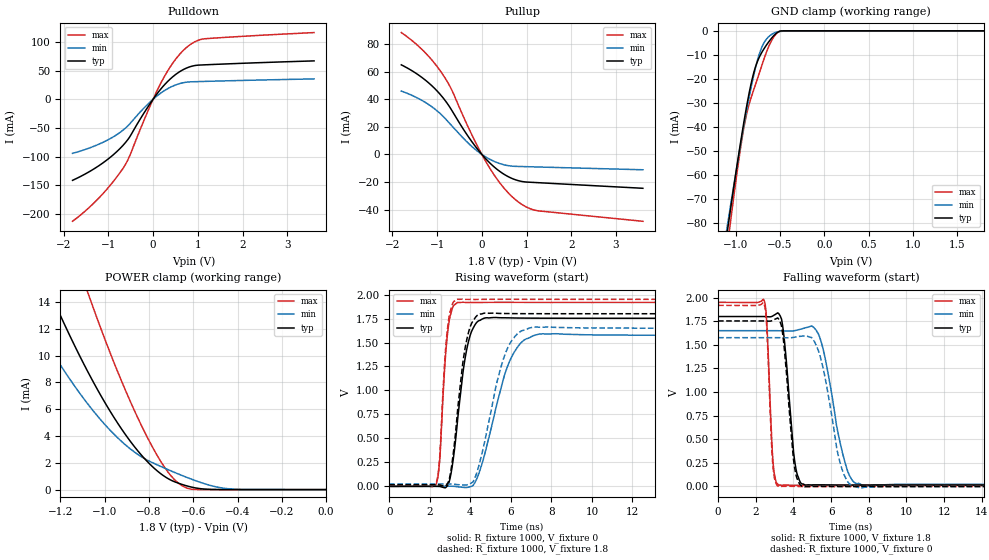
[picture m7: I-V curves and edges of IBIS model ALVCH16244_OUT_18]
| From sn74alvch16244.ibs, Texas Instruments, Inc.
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[Model]   ALVCH16244_OUT_18
Model_type  3-state
Enable   Active-Low
Vref =   0
Rref =   1000
Cref =   30p
Vmeas =   0.9
| variable   typ   min   max
C_comp   7.36pF   6.56pF   8.29pF
| C_pullup   8.44pF   7.01pF   9.20pF
| C_pulldown   11.41pF   8.44pF   14.80pF
| C_tri-state   7.36pF   6.56pF   8.29pF
[Temperature Range]   40   100   -40
| Ambient temperature   25   85   -40
[Voltage range]   1.8   1.65   1.95
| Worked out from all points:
|   slope of the pulldown table from 0 to 0.27 V, typ, clamps not added: 10.2 ohm
|   slope of the pullup table from 0 to 0.27 V, typ, clamps not added: 30.2 ohm
|   GND clamp passes 1 mA (typ) near -0.54 V on its own axis
|   POWER clamp passes 1 mA (typ) near -0.73 V on its own axis
|   rising waveform, R_fixture 1000, V_fixture 0: 20-80 % time 601ps typ, 1.17ns min, 324ps max; typ from 0 V to 1.75 V
|   falling waveform, R_fixture 1000, V_fixture 1.8: 20-80 % time 434ps typ, 895ps min, 245ps max; typ from 1.8 V to 0.016 V
|   rising waveform, R_fixture 1000, V_fixture 1.8: 20-80 % time 569ps typ, 1.05ns min, 316ps max; typ from 0.016 V to 1.8 V
|   falling waveform, R_fixture 1000, V_fixture 0: 20-80 % time 433ps typ, 831ps min, 234ps max; typ from 1.75 V to 0 V
[GND Clamp]
| ALVCH16244_OUT_18
|   Voltage   I(typ)   I(min)   I(max)
-1.8V     -279.2mA   -258.4mA   -312.7mA
-1.09V    -82.1mA    -79.94mA   -88.35mA
-1.075V   -78.25mA   -76.44mA   -83.98mA
-1.055V   -73.15mA   -71.81mA   -78.22mA
-915mV    -39.48mA   -40.86mA   -41.77mA
-870mV    -29.95mA   -31.73mA   -33.49mA
-815mV    -20.09mA   -21.51mA   -26.49mA
-765mV    -13.71mA   -13.6mA    -21.01mA
-710mV    -9.262mA   -7.21mA    -14.9mA
-585mV    -2.6mA     -1.263mA   -3.417mA
-485mV    -33.17uA   -215.5uA   -23.48uA
1.8V      60.47pA    9.424nA    28.01pA
[POWER Clamp]
| ALVCH16244_OUT_18
|   Voltage   I(typ)   I(min)   I(max)
-1.8V     39.51mA    28.78mA    57.18mA
-1.39V    20.42mA    14.63mA    31.28mA
-1.23V    14.08mA    10.07mA    22.39mA
-1.08V    8.91mA     6.466mA    14.87mA
-1.065V   8.441mA    6.147mA    14.17mA
-955mV    5.302mA    4.082mA    9.347mA
-860mV    3.083mA    2.735mA    5.684mA
-750mV    1.224mA    1.751mA    2.186mA
-665mV    466.1uA    1.149mA    454.2uA
-610mV    194.7uA    789.6uA    32.77uA
-455mV    1.47uA     87.26uA    53.39nA
-16.28fV  60.47pA    287pA      33.61pA
[Pulldown]
| ALVCH16244_OUT_18
|   Voltage   I(typ)   I(min)   I(max)
-1.8V     -141.4mA   -94.33mA   -212.9mA
-1.195V   -115mA     -77.76mA   -171mA
-905mV    -97.86mA   -66.26mA   -145mA
-665mV    -79.81mA   -53.39mA   -119.8mA
-530mV    -66.51mA   -43.55mA   -100.1mA
-105mV    -12.13mA   -7.634mA   -18.73mA
200mV     20.41mA    12.38mA    32.16mA
495mV     42.75mA    24.8mA     68.98mA
790mV     55.87mA    30.28mA    93.18mA
970mV     59.35mA    30.84mA    101.8mA
1.155V    60.2mA     31.26mA    105.7mA
3.6V      67.09mA    35.62mA    116.5mA
[Pullup]
| ALVCH16244_OUT_18
|   Voltage   I(typ)   I(min)   I(max)
-1.8V     64.98mA    45.95mA    88.4mA
-1.305V   54.98mA    38.53mA    75.09mA
-1.09V    48.97mA    33.9mA     67.43mA
-900mV    42.35mA    28.69mA    59.27mA
-675mV    32.13mA    20.88mA    46.91mA
-280mV    11.84mA    7.43mA     18.08mA
120mV     -4.3mA     -2.474mA   -6.918mA
455mV     -13.55mA   -7.178mA   -22.84mA
795mV     -18.85mA   -8.713mA   -33.97mA
1.025V    -20.11mA   -8.923mA   -38.62mA
1.255V    -20.5mA    -9.129mA   -40.95mA
3.6V      -24.58mA   -11.14mA   -48.53mA
[Ramp]
| ALVCH16244_OUT_18
| variable   typ   min   max
dV/dt_r   1.06/6.34E-10   0.96/1.25E-09   1.15/3.31E-10
dV/dt_f   1.09/4.48E-10   1.01/1.00E-09   1.18/2.52E-10
R_load = 1000
[Rising Waveform]
| ALVCH16244_OUT_18
R_fixture =   1000
C_fixture =   0
L_fixture =   0
V_fixture =   0
V_fixture_min = 0
V_fixture_max = 0
|   Time   V(typ)   V(min)   V(max)
0s        316.9pV    1.692nV    220.5pV
2.32ns    670.7uV    236.4uV    23.89mV
2.5ns     -1.241mV   1.195mV    301.7mV
2.895ns   16.62mV    1.644mV    1.628V
3.39ns    730.7mV    -4.61mV    1.918V
3.815ns   1.419V     -12.14mV   1.918V
4.3ns     1.706V     69.65mV    1.917V
5.94ns    1.757V     1.306V     1.919V
7.395ns   1.754V     1.588V     1.918V
50ns      1.753V     1.576V     1.918V
[Falling Waveform]
| ALVCH16244_OUT_18
R_fixture =   1000
C_fixture =   0
L_fixture =   0
V_fixture =   1.8
V_fixture_min = 1.65
V_fixture_max = 1.95
|   Time   V(typ)   V(min)   V(max)
0s        1.8V       1.65V      1.95V
2.455ns   1.8V       1.65V      1.963V
2.92ns    1.808V     1.65V      255.2mV
3.235ns   1.827V     1.649V     13.86mV
4.09ns    238.3mV    1.652V     12.47mV
4.635ns   14.65mV    1.68V      11.07mV
5.475ns   17.28mV    1.53V      10.76mV
6.88ns    15.66mV    160.6mV    10.97mV
7.805ns   15.64mV    5.683mV    11.06mV
50ns      15.91mV    23.52mV    11.08mV
[Rising Waveform]
| ALVCH16244_OUT_18
R_fixture =   1000
C_fixture =   0
L_fixture =   0
V_fixture =   1.8
V_fixture_min = 1.65
V_fixture_max = 1.95
|   Time   V(typ)   V(min)   V(max)
0s        15.91mV    23.52mV    11.08mV
2.32ns    16.16mV    23.76mV    36.86mV
2.495ns   14.24mV    24.48mV    319mV
2.885ns   33.49mV    24.16mV    1.666V
3.38ns    811.5mV    18.25mV    1.952V
3.785ns   1.489V     13.59mV    1.95V
4.265ns   1.766V     108.8mV    1.949V
5.725ns   1.802V     1.384V     1.951V
7.07ns    1.8V       1.659V     1.95V
50ns      1.8V       1.65V      1.95V
[Falling Waveform]
| ALVCH16244_OUT_18
R_fixture =   1000
C_fixture =   0
L_fixture =   0
V_fixture =   0
V_fixture_min = 0
V_fixture_max = 0
|   Time   V(typ)   V(min)   V(max)
0s        1.753V     1.576V     1.918V
2.45ns    1.753V     1.576V     1.928V
2.895ns   1.758V     1.576V     259.7mV
3.18ns    1.782V     1.576V     3.239mV
4.065ns   198.6mV    1.581V     1.222mV
4.59ns    -2.9mV     1.594V     -35.99uV
5.42ns    911.6uV    1.377V     -328.6uV
6.615ns   -233.9uV   162.2mV    -123.9uV
7.48ns    -259.9uV   -12.72mV   -33.54uV
50ns      2.599nV    -2.337nV   -4.936nV
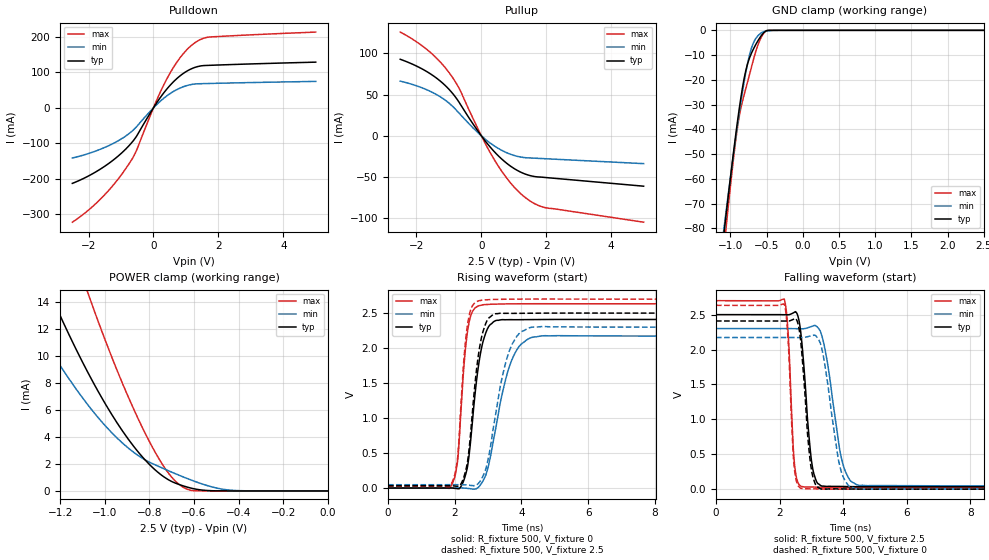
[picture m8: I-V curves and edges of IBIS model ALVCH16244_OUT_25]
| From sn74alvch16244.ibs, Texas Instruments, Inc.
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[Model]   ALVCH16244_OUT_25
Model_type  3-state
Enable   Active-Low
Vref =   0
Rref =   500
Cref =   30p
Vmeas =   1.25
| variable   typ   min   max
C_comp   7.09pF   6.28pF   8.16pF
| C_pullup   8.26pF   6.89pF   9.11pF
| C_pulldown   10.90pF   8.43pF   13.84pF
| C_tri-state   7.09pF   6.28pF   8.16pF
[Temperature Range]   40   100   -40
| Ambient temperature   25   85   -40
[Voltage range]   2.5   2.3   2.7
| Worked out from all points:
|   slope of the pulldown table from 0 to 0.375 V, typ, clamps not added: 7.65 ohm
|   slope of the pullup table from 0 to 0.375 V, typ, clamps not added: 20.6 ohm
|   GND clamp passes 1 mA (typ) near -0.54 V on its own axis
|   POWER clamp passes 1 mA (typ) near -0.73 V on its own axis
|   rising waveform, R_fixture 500, V_fixture 0: 20-80 % time 340ps typ, 575ps min, 236ps max; typ from 0 V to 2.41 V
|   falling waveform, R_fixture 500, V_fixture 2.5: 20-80 % time 255ps typ, 430ps min, 157ps max; typ from 2.5 V to 0.034 V
|   rising waveform, R_fixture 500, V_fixture 2.5: 20-80 % time 321ps typ, 525ps min, 230ps max; typ from 0.034 V to 2.5 V
|   falling waveform, R_fixture 500, V_fixture 0: 20-80 % time 241ps typ, 407ps min, 154ps max; typ from 2.41 V to 0 V
[GND Clamp]
| ALVCH16244_OUT_25
|   Voltage   I(typ)   I(min)   I(max)
-2.5V     -484.4mA   -444.2mA   -546.2mA
-1.085V   -80.82mA   -78.77mA   -86.89mA
-1.07V    -76.97mA   -75.28mA   -82.53mA
-1.05V    -71.89mA   -70.66mA   -76.79mA
-915mV    -39.48mA   -40.86mA   -41.77mA
-870mV    -29.95mA   -31.73mA   -33.49mA
-810mV    -19.33mA   -20.65mA   -25.93mA
-755mV    -12.74mA   -12.24mA   -19.91mA
-700mV    -8.616mA   -6.354mA   -13.78mA
-560mV    -1.618mA   -798.8uA   -2.03mA
-485mV    -33.17uA   -215.5uA   -23.48uA
2.5V      83.81pA    43.81nA    39.19pA
[POWER Clamp]
| ALVCH16244_OUT_25
|   Voltage   I(typ)   I(min)   I(max)
-2.5V     78.16mA    58.07mA    108.2mA
-1.385V   20.21mA    14.48mA    30.99mA
-1.24V    14.46mA    10.33mA    22.92mA
-1.08V    8.91mA     6.466mA    14.87mA
-1.065V   8.441mA    6.147mA    14.17mA
-945mV    5.045mA    3.92mA     8.938mA
-855mV    2.981mA    2.677mA    5.506mA
-755mV    1.289mA    1.788mA    2.322mA
-670mV    495.5uA    1.183mA    520.4uA
-605mV    175.7uA    758.6uA    22.19uA
-445mV    1.019uA    68.56uA    35.87nA
-31.15fV  83.81pA    322.9pA    46.7pA
[Pulldown]
| ALVCH16244_OUT_25
|   Voltage   I(typ)   I(min)   I(max)
-2.5V     -213.5mA   -141.7mA   -323.1mA
-1.595V   -170.7mA   -115.5mA   -254.3mA
-1.18V    -143.3mA   -97.74mA   -211.7mA
-805mV    -111.9mA   -76.42mA   -165.1mA
-545mV    -83.42mA   -55.66mA   -124.8mA
70mV      10.13mA    6.566mA    15.4mA
425mV     54.54mA    34.7mA     83.99mA
820mV     90.47mA    55.98mA    141.7mA
1.215V    112.2mA    66.71mA    179.9mA
1.465V    118.6mA    68.28mA    193.9mA
1.72V     120.2mA    68.88mA    200.2mA
5V        129.2mA    74.77mA    214.1mA
[Pullup]
| ALVCH16244_OUT_25
|   Voltage   I(typ)   I(min)   I(max)
-2.5V     92.96mA    66.45mA    126mA
-1.66V    77.48mA    55.56mA    104.2mA
-1.315V   68.02mA    48.56mA    91.64mA
-1.01V    56.98mA    40.11mA    77.55mA
-685mV    40.61mA    27.47mA    57.59mA
15mV      -812.9uA   -531.7uA   -1.2mA
425mV     -20.36mA   -12.93mA   -30.68mA
890mV     -36.57mA   -22.24mA   -56.75mA
1.36V     -46.54mA   -26.55mA   -75.17mA
1.67V     -49.6mA    -27.19mA   -82.95mA
1.985V    -50.63mA   -27.82mA   -87.32mA
5V        -61.14mA   -33.76mA   -104.8mA
[Ramp]
| ALVCH16244_OUT_25
| variable   typ   min   max
dV/dt_r   1.45/3.59E-10   1.31/6.10E-10   1.58/2.45E-10
dV/dt_f   1.51/2.67E-10   1.38/4.57E-10   1.62/1.64E-10
R_load = 500
[Rising Waveform]
| ALVCH16244_OUT_25
R_fixture =   500
C_fixture =   0
L_fixture =   0
V_fixture =   0
V_fixture_min = 0
V_fixture_max = 0
|   Time   V(typ)   V(min)   V(max)
0s        334.1pV    1.357nV    238.1pV
1.905ns   719.6uV    941uV      41.48mV
2.09ns    -8.839mV   1.385mV    406.2mV
2.275ns   114.7mV    -153.8uV   1.741V
2.41ns    396.4mV    -6.131mV   2.318V
2.68ns    1.638V     14.03uV    2.596V
2.885ns   2.152V     136.8mV    2.621V
3.705ns   2.407V     1.824V     2.632V
4.625ns   2.409V     2.175V     2.634V
50ns      2.409V     2.172V     2.633V
[Falling Waveform]
| ALVCH16244_OUT_25
R_fixture =   500
C_fixture =   0
L_fixture =   0
V_fixture =   2.5
V_fixture_min = 2.3
V_fixture_max = 2.7
|   Time   V(typ)   V(min)   V(max)
0s        2.5V       2.3V       2.7V
2.15ns    2.499V     2.3V       2.72V
2.275ns   2.498V     2.3V       2.208V
2.475ns   2.536V     2.299V     345.4mV
2.78ns    1.687V     2.299V     31.05mV
2.99ns    465.6mV    2.327V     30.15mV
3.165ns   109.2mV    2.333V     28.64mV
3.99ns    37.97mV    369mV      24.15mV
4.52ns    34.71mV    52.74mV    23.69mV
50ns      33.7mV     47.62mV    23.99mV
[Rising Waveform]
| ALVCH16244_OUT_25
R_fixture =   500
C_fixture =   0
L_fixture =   0
V_fixture =   2.5
V_fixture_min = 2.3
V_fixture_max = 2.7
|   Time   V(typ)   V(min)   V(max)
0s        33.7mV     47.62mV    23.99mV
1.9ns     33.97mV    48.18mV    63.08mV
2.085ns   25.46mV    48.14mV    433.7mV
2.265ns   144.7mV    46.52mV    1.783V
2.4ns     436.4mV    41.58mV    2.389V
2.665ns   1.743V     48.05mV    2.665V
2.87ns    2.27V      197.2mV    2.688V
3.605ns   2.497V     1.917V     2.699V
4.345ns   2.499V     2.301V     2.701V
50ns      2.5V       2.3V       2.7V
[Falling Waveform]
| ALVCH16244_OUT_25
R_fixture =   500
C_fixture =   0
L_fixture =   0
V_fixture =   0
V_fixture_min = 0
V_fixture_max = 0
|   Time   V(typ)   V(min)   V(max)
0s        2.409V     2.172V     2.633V
2.15ns    2.408V     2.172V     2.649V
2.265ns   2.408V     2.172V     2.174V
2.47ns    2.44V      2.172V     287mV
2.77ns    1.558V     2.173V     5.275mV
2.955ns   449.1mV    2.193V     4.647mV
3.135ns   64.09mV    2.199V     3.982mV
3.92ns    3.417mV    291mV      123.8uV
4.43ns    929.3uV    2.071mV    -291.9uV
50ns      1.449nV    -2.788nV   -1.669nV
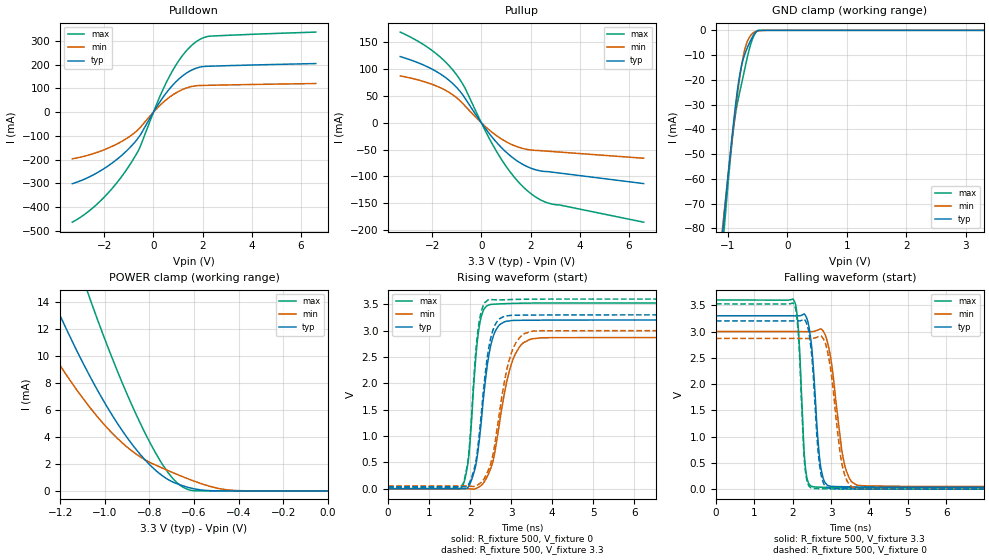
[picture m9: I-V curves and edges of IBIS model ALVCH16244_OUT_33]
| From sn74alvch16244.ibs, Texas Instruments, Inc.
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[Model]   ALVCH16244_OUT_33
Model_type  3-state
Enable   Active-Low
Vref =   0
Rref =   500
Cref =   50p
Vmeas =   1.5
| variable   typ   min   max
C_comp   6.83pF   5.99pF   8.09pF
| C_pullup   7.96pF   6.08pF   8.98pF
| C_pulldown   10.61pF   8.38pF   13.69pF
| C_tri-state   6.83pF   5.99pF   8.09pF
[Temperature Range]   40   100   -40
| Ambient temperature   25   85   -40
[Voltage range]   3.3   3   3.6
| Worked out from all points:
|   slope of the pulldown table from 0 to 0.495 V, typ, clamps not added: 6.36 ohm
|   slope of the pullup table from 0 to 0.495 V, typ, clamps not added: 16.5 ohm
|   GND clamp passes 1 mA (typ) near -0.54 V on its own axis
|   POWER clamp passes 1 mA (typ) near -0.73 V on its own axis
|   rising waveform, R_fixture 500, V_fixture 0: 20-80 % time 285ps typ, 406ps min, 201ps max; typ from 0 V to 3.2 V
|   falling waveform, R_fixture 500, V_fixture 3.3: 20-80 % time 185ps typ, 294ps min, 133ps max; typ from 3.3 V to 0.037 V
|   rising waveform, R_fixture 500, V_fixture 3.3: 20-80 % time 277ps typ, 387ps min, 198ps max; typ from 0.037 V to 3.3 V
|   falling waveform, R_fixture 500, V_fixture 0: 20-80 % time 179ps typ, 275ps min, 131ps max; typ from 3.2 V to 0 V
[GND Clamp]
| ALVCH16244_OUT_33
|   Voltage   I(typ)   I(min)   I(max)
-3.3V     -723.6mA   -660.8mA   -818.5mA
-1.105V   -85.98mA   -83.46mA   -92.75mA
-1.08V    -79.53mA   -77.6mA    -85.43mA
-1.06V    -74.42mA   -72.96mA   -79.65mA
-905mV    -37.28mA   -38.78mA   -39.69mA
-805mV    -18.6mA    -19.8mA    -25.38mA
-750mV    -12.29mA   -11.59mA   -19.37mA
-690mV    -7.998mA   -5.589mA   -12.67mA
-620mV    -4.201mA   -2.181mA   -5.912mA
-545mV    -1.117mA   -590.7uA   -1.362mA
-480mV    -21.29uA   -197.7uA   -14.88uA
3.3V      114.4pA    972nA      51.31pA
[POWER Clamp]
| ALVCH16244_OUT_33
|   Voltage   I(typ)   I(min)   I(max)
-3.3V     127.6mA    95.87mA    172.6mA
-1.385V   20.21mA    14.48mA    30.99mA
-1.235V   14.27mA    10.2mA     22.65mA
-1.1V     9.551mA    6.903mA    15.82mA
-1.065V   8.441mA    6.147mA    14.17mA
-960mV    5.432mA    4.165mA    9.553mA
-860mV    3.083mA    2.735mA    5.684mA
-750mV    1.224mA    1.751mA    2.186mA
-665mV    466.1uA    1.149mA    454.2uA
-600mV    157.8uA    727.9uA    16.25uA
-450mV    1.224uA    77.47uA    43.78nA
-48.03fV  114.4pA    365.2pA    62.68pA
[Pulldown]
| ALVCH16244_OUT_33
|   Voltage   I(typ)   I(min)   I(max)
-3.3V     -301.6mA   -196.5mA   -463.9mA
-2.725V   -278.6mA   -183.3mA   -425.2mA
-2.155V   -247.3mA   -164.4mA   -374.1mA
-1.6V     -208.1mA   -140mA     -311.9mA
-1.085V   -162.5mA   -110.4mA   -241.1mA
-570mV    -101.4mA   -67.91mA   -152.4mA
185mV     31.43mA    20.51mA    47.78mA
670mV     100.6mA    64.5mA     154.8mA
1.17V     151.9mA    95.01mA    237.4mA
1.67V     182.8mA    110.5mA    291.9mA
2.31V     194mA      113.5mA    320.7mA
6.6V      205mA      120.8mA    337.8mA
[Pullup]
| ALVCH16244_OUT_33
|   Voltage   I(typ)   I(min)   I(max)
-3.3V     123.5mA    87.44mA    169.1mA
-2.045V   101mA      72.4mA     136.2mA
-1.55V    87.39mA    62.74mA    117.4mA
-1.13V    71.66mA    51.07mA    96.68mA
-685mV    47.27mA    32.42mA    66.38mA
180mV     -11.59mA   -7.766mA   -16.76mA
760mV     -43.54mA   -28.44mA   -64.12mA
1.38V     -68.63mA   -43.29mA   -103.6mA
2V        -84.39mA   -50.65mA   -131.6mA
2.405V    -89.66mA   -51.96mA   -143.6mA
2.81V     -91.58mA   -53.32mA   -150.8mA
6.6V      -113.3mA   -66.05mA   -185.3mA
[Ramp]
| ALVCH16244_OUT_33
| variable   typ   min   max
dV/dt_r   1.92/2.97E-10   1.73/4.11E-10   2.12/2.10E-10
dV/dt_f   1.98/1.89E-10   1.80/3.13E-10   2.16/1.38E-10
R_load = 500
[Rising Waveform]
| ALVCH16244_OUT_33
R_fixture =   500
C_fixture =   0
L_fixture =   0
V_fixture =   0
V_fixture_min = 0
V_fixture_max = 0
|   Time   V(typ)   V(min)   V(max)
0s        368pV      1.242nV    265.6pV
1.825ns   -1.923mV   2.167mV    60.24mV
1.965ns   46.55mV    -559.7uV   594.8mV
2.14ns    446.6mV    3.28mV     2.5V
2.225ns   925.8mV    37.01mV    3.083V
2.405ns   2.257V     210.4mV    3.469V
2.535ns   2.816V     458mV      3.5V
3.05ns    3.195V     2.462V     3.518V
3.73ns    3.2V       2.865V     3.525V
50ns      3.202V     2.869V     3.526V
[Falling Waveform]
| ALVCH16244_OUT_33
R_fixture =   500
C_fixture =   0
L_fixture =   0
V_fixture =   3.3
V_fixture_min = 3
V_fixture_max = 3.6
|   Time   V(typ)   V(min)   V(max)
0s        3.3V       3V         3.6V
2.03ns    3.298V     3V         3.594V
2.15ns    3.3V       2.999V     3.025V
2.33ns    3.307V     2.998V     422.1mV
2.585ns   1.786V     3.009V     41.49mV
2.7ns     598.1mV    3.042V     37.61mV
2.825ns   146.8mV    2.97V      34.87mV
3.36ns    45.91mV    443.9mV    28.28mV
3.82ns    39.78mV    63.67mV    26.83mV
50ns      37.06mV    51.27mV    26.72mV
[Rising Waveform]
| ALVCH16244_OUT_33
R_fixture =   500
C_fixture =   0
L_fixture =   0
V_fixture =   3.3
V_fixture_min = 3
V_fixture_max = 3.6
|   Time   V(typ)   V(min)   V(max)
0s        37.06mV    51.27mV    26.72mV
1.825ns   34.83mV    52.74mV    88.3mV
1.965ns   86.2mV     49.76mV    645.5mV
2.13ns    468.1mV    52.08mV    2.508V
2.205ns   897.4mV    81.75mV    3.083V
2.475ns   2.756V     412.7mV    3.592V
2.67ns    3.183V     1.195V     3.585V
2.985ns   3.289V     2.521V     3.591V
3.545ns   3.296V     2.993V     3.599V
50ns      3.3V       3V         3.6V
[Falling Waveform]
| ALVCH16244_OUT_33
R_fixture =   500
C_fixture =   0
L_fixture =   0
V_fixture =   0
V_fixture_min = 0
V_fixture_max = 0
|   Time   V(typ)   V(min)   V(max)
0s        3.202V     2.869V     3.526V
2.03ns    3.201V     2.869V     3.518V
2.15ns    3.202V     2.868V     2.926V
2.325ns   3.211V     2.867V     379.2mV
2.535ns   2.166V     2.871V     14.86mV
2.67ns    660.1mV    2.901V     9.916mV
2.8ns     117.1mV    2.859V     7.415mV
3.305ns   6.71mV     405.2mV    1.579mV
3.71ns    2.841mV    9.198mV    197uV
50ns      -3.973nV   6.682nV    -1.666nV
